VERSION 5.7 ;
  NOWIREEXTENSIONATPIN ON ;
  DIVIDERCHAR "/" ;
  BUSBITCHARS "[]" ;
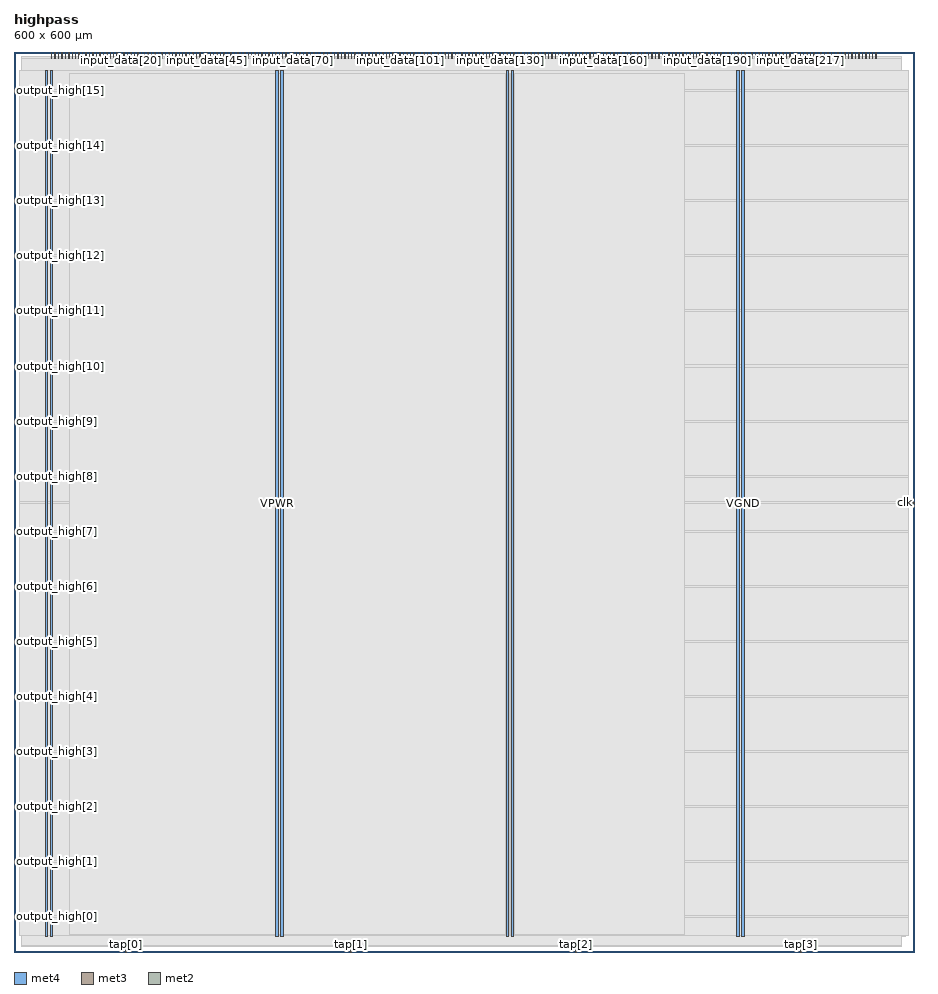
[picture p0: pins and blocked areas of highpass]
MACRO highpass
  CLASS BLOCK ;
  FOREIGN highpass ;
  ORIGIN 0.000 0.000 ;
  SIZE 600.000 BY 600.000 ;
  PIN VGND
    DIRECTION INOUT ;
    USE GROUND ;
    PORT
      LAYER met4 ;
        RECT 24.340 10.640 25.940 587.760 ;
    END
    PORT
      LAYER met4 ;
        RECT 177.940 10.640 179.540 587.760 ;
    END
    PORT
      LAYER met4 ;
        RECT 331.540 10.640 333.140 587.760 ;
    END
    PORT
      LAYER met4 ;
        RECT 485.140 10.640 486.740 587.760 ;
    END
  END VGND
  PIN VPWR
    DIRECTION INOUT ;
    USE POWER ;
    PORT
      LAYER met4 ;
        RECT 21.040 10.640 22.640 587.760 ;
    END
    PORT
      LAYER met4 ;
        RECT 174.640 10.640 176.240 587.760 ;
    END
    PORT
      LAYER met4 ;
        RECT 328.240 10.640 329.840 587.760 ;
    END
    PORT
      LAYER met4 ;
        RECT 481.840 10.640 483.440 587.760 ;
    END
  END VPWR
  PIN clk
    DIRECTION INPUT ;
    USE SIGNAL ;
    ANTENNAGATEAREA 0.852000 ;
    ANTENNADIFFAREA 0.434700 ;
    PORT
      LAYER met3 ;
        RECT 596.000 299.240 600.000 299.840 ;
    END
  END clk
  PIN input_data[0]
    DIRECTION INPUT ;
    USE SIGNAL ;
    ANTENNAGATEAREA 0.247500 ;
    ANTENNADIFFAREA 0.434700 ;
    PORT
      LAYER met2 ;
        RECT 24.930 596.000 25.210 600.000 ;
    END
  END input_data[0]
  PIN input_data[100]
    DIRECTION INPUT ;
    USE SIGNAL ;
    ANTENNAGATEAREA 0.213000 ;
    ANTENNADIFFAREA 0.434700 ;
    PORT
      LAYER met2 ;
        RECT 254.930 596.000 255.210 600.000 ;
    END
  END input_data[100]
  PIN input_data[101]
    DIRECTION INPUT ;
    USE SIGNAL ;
    ANTENNAGATEAREA 0.196500 ;
    ANTENNADIFFAREA 0.434700 ;
    PORT
      LAYER met2 ;
        RECT 257.230 596.000 257.510 600.000 ;
    END
  END input_data[101]
  PIN input_data[102]
    DIRECTION INPUT ;
    USE SIGNAL ;
    ANTENNAGATEAREA 0.196500 ;
    ANTENNADIFFAREA 0.434700 ;
    PORT
      LAYER met2 ;
        RECT 259.530 596.000 259.810 600.000 ;
    END
  END input_data[102]
  PIN input_data[103]
    DIRECTION INPUT ;
    USE SIGNAL ;
    ANTENNAGATEAREA 0.196500 ;
    ANTENNADIFFAREA 0.434700 ;
    PORT
      LAYER met2 ;
        RECT 261.830 596.000 262.110 600.000 ;
    END
  END input_data[103]
  PIN input_data[104]
    DIRECTION INPUT ;
    USE SIGNAL ;
    ANTENNAGATEAREA 0.196500 ;
    ANTENNADIFFAREA 0.434700 ;
    PORT
      LAYER met2 ;
        RECT 264.130 596.000 264.410 600.000 ;
    END
  END input_data[104]
  PIN input_data[105]
    DIRECTION INPUT ;
    USE SIGNAL ;
    ANTENNAGATEAREA 0.196500 ;
    ANTENNADIFFAREA 0.434700 ;
    PORT
      LAYER met2 ;
        RECT 266.430 596.000 266.710 600.000 ;
    END
  END input_data[105]
  PIN input_data[106]
    DIRECTION INPUT ;
    USE SIGNAL ;
    ANTENNAGATEAREA 0.196500 ;
    ANTENNADIFFAREA 0.434700 ;
    PORT
      LAYER met2 ;
        RECT 268.730 596.000 269.010 600.000 ;
    END
  END input_data[106]
  PIN input_data[107]
    DIRECTION INPUT ;
    USE SIGNAL ;
    ANTENNAGATEAREA 0.196500 ;
    ANTENNADIFFAREA 0.434700 ;
    PORT
      LAYER met2 ;
        RECT 271.030 596.000 271.310 600.000 ;
    END
  END input_data[107]
  PIN input_data[108]
    DIRECTION INPUT ;
    USE SIGNAL ;
    ANTENNAGATEAREA 0.213000 ;
    ANTENNADIFFAREA 0.434700 ;
    PORT
      LAYER met2 ;
        RECT 273.330 596.000 273.610 600.000 ;
    END
  END input_data[108]
  PIN input_data[109]
    DIRECTION INPUT ;
    USE SIGNAL ;
    ANTENNAGATEAREA 0.126000 ;
    ANTENNADIFFAREA 0.434700 ;
    PORT
      LAYER met2 ;
        RECT 275.630 596.000 275.910 600.000 ;
    END
  END input_data[109]
  PIN input_data[10]
    DIRECTION INPUT ;
    USE SIGNAL ;
    ANTENNAGATEAREA 0.247500 ;
    ANTENNADIFFAREA 0.434700 ;
    PORT
      LAYER met2 ;
        RECT 47.930 596.000 48.210 600.000 ;
    END
  END input_data[10]
  PIN input_data[110]
    DIRECTION INPUT ;
    USE SIGNAL ;
    ANTENNAGATEAREA 0.196500 ;
    ANTENNADIFFAREA 0.434700 ;
    PORT
      LAYER met2 ;
        RECT 277.930 596.000 278.210 600.000 ;
    END
  END input_data[110]
  PIN input_data[111]
    DIRECTION INPUT ;
    USE SIGNAL ;
    ANTENNAGATEAREA 0.196500 ;
    ANTENNADIFFAREA 0.434700 ;
    PORT
      LAYER met2 ;
        RECT 280.230 596.000 280.510 600.000 ;
    END
  END input_data[111]
  PIN input_data[112]
    DIRECTION INPUT ;
    USE SIGNAL ;
    ANTENNAGATEAREA 0.213000 ;
    ANTENNADIFFAREA 0.434700 ;
    PORT
      LAYER met2 ;
        RECT 282.530 596.000 282.810 600.000 ;
    END
  END input_data[112]
  PIN input_data[113]
    DIRECTION INPUT ;
    USE SIGNAL ;
    ANTENNAGATEAREA 0.126000 ;
    ANTENNADIFFAREA 0.434700 ;
    PORT
      LAYER met2 ;
        RECT 284.830 596.000 285.110 600.000 ;
    END
  END input_data[113]
  PIN input_data[114]
    DIRECTION INPUT ;
    USE SIGNAL ;
    ANTENNAGATEAREA 0.126000 ;
    ANTENNADIFFAREA 0.434700 ;
    PORT
      LAYER met2 ;
        RECT 287.130 596.000 287.410 600.000 ;
    END
  END input_data[114]
  PIN input_data[115]
    DIRECTION INPUT ;
    USE SIGNAL ;
    ANTENNAGATEAREA 0.196500 ;
    ANTENNADIFFAREA 0.434700 ;
    PORT
      LAYER met2 ;
        RECT 289.430 596.000 289.710 600.000 ;
    END
  END input_data[115]
  PIN input_data[116]
    DIRECTION INPUT ;
    USE SIGNAL ;
    ANTENNAGATEAREA 0.196500 ;
    ANTENNADIFFAREA 0.434700 ;
    PORT
      LAYER met2 ;
        RECT 291.730 596.000 292.010 600.000 ;
    END
  END input_data[116]
  PIN input_data[117]
    DIRECTION INPUT ;
    USE SIGNAL ;
    ANTENNAGATEAREA 0.196500 ;
    ANTENNADIFFAREA 0.434700 ;
    PORT
      LAYER met2 ;
        RECT 294.030 596.000 294.310 600.000 ;
    END
  END input_data[117]
  PIN input_data[118]
    DIRECTION INPUT ;
    USE SIGNAL ;
    ANTENNAGATEAREA 0.196500 ;
    ANTENNADIFFAREA 0.434700 ;
    PORT
      LAYER met2 ;
        RECT 296.330 596.000 296.610 600.000 ;
    END
  END input_data[118]
  PIN input_data[119]
    DIRECTION INPUT ;
    USE SIGNAL ;
    ANTENNAGATEAREA 0.196500 ;
    ANTENNADIFFAREA 0.434700 ;
    PORT
      LAYER met2 ;
        RECT 298.630 596.000 298.910 600.000 ;
    END
  END input_data[119]
  PIN input_data[11]
    DIRECTION INPUT ;
    USE SIGNAL ;
    ANTENNAGATEAREA 0.159000 ;
    ANTENNADIFFAREA 0.434700 ;
    PORT
      LAYER met2 ;
        RECT 50.230 596.000 50.510 600.000 ;
    END
  END input_data[11]
  PIN input_data[120]
    DIRECTION INPUT ;
    USE SIGNAL ;
    ANTENNAGATEAREA 0.213000 ;
    ANTENNADIFFAREA 0.434700 ;
    PORT
      LAYER met2 ;
        RECT 300.930 596.000 301.210 600.000 ;
    END
  END input_data[120]
  PIN input_data[121]
    DIRECTION INPUT ;
    USE SIGNAL ;
    ANTENNAGATEAREA 0.126000 ;
    ANTENNADIFFAREA 0.434700 ;
    PORT
      LAYER met2 ;
        RECT 303.230 596.000 303.510 600.000 ;
    END
  END input_data[121]
  PIN input_data[122]
    DIRECTION INPUT ;
    USE SIGNAL ;
    ANTENNAGATEAREA 0.159000 ;
    ANTENNADIFFAREA 0.434700 ;
    PORT
      LAYER met2 ;
        RECT 305.530 596.000 305.810 600.000 ;
    END
  END input_data[122]
  PIN input_data[123]
    DIRECTION INPUT ;
    USE SIGNAL ;
    ANTENNAGATEAREA 0.159000 ;
    ANTENNADIFFAREA 0.434700 ;
    PORT
      LAYER met2 ;
        RECT 307.830 596.000 308.110 600.000 ;
    END
  END input_data[123]
  PIN input_data[124]
    DIRECTION INPUT ;
    USE SIGNAL ;
    ANTENNAGATEAREA 0.213000 ;
    ANTENNADIFFAREA 0.434700 ;
    PORT
      LAYER met2 ;
        RECT 310.130 596.000 310.410 600.000 ;
    END
  END input_data[124]
  PIN input_data[125]
    DIRECTION INPUT ;
    USE SIGNAL ;
    ANTENNAGATEAREA 0.196500 ;
    ANTENNADIFFAREA 0.434700 ;
    PORT
      LAYER met2 ;
        RECT 312.430 596.000 312.710 600.000 ;
    END
  END input_data[125]
  PIN input_data[126]
    DIRECTION INPUT ;
    USE SIGNAL ;
    ANTENNAGATEAREA 0.196500 ;
    ANTENNADIFFAREA 0.434700 ;
    PORT
      LAYER met2 ;
        RECT 314.730 596.000 315.010 600.000 ;
    END
  END input_data[126]
  PIN input_data[127]
    DIRECTION INPUT ;
    USE SIGNAL ;
    PORT
      LAYER met2 ;
        RECT 317.030 596.000 317.310 600.000 ;
    END
  END input_data[127]
  PIN input_data[128]
    DIRECTION INPUT ;
    USE SIGNAL ;
    ANTENNAGATEAREA 0.213000 ;
    ANTENNADIFFAREA 0.434700 ;
    PORT
      LAYER met2 ;
        RECT 319.330 596.000 319.610 600.000 ;
    END
  END input_data[128]
  PIN input_data[129]
    DIRECTION INPUT ;
    USE SIGNAL ;
    ANTENNAGATEAREA 0.213000 ;
    ANTENNADIFFAREA 0.434700 ;
    PORT
      LAYER met2 ;
        RECT 321.630 596.000 321.910 600.000 ;
    END
  END input_data[129]
  PIN input_data[12]
    DIRECTION INPUT ;
    USE SIGNAL ;
    ANTENNAGATEAREA 0.742500 ;
    ANTENNADIFFAREA 0.434700 ;
    PORT
      LAYER met2 ;
        RECT 52.530 596.000 52.810 600.000 ;
    END
  END input_data[12]
  PIN input_data[130]
    DIRECTION INPUT ;
    USE SIGNAL ;
    ANTENNAGATEAREA 0.159000 ;
    ANTENNADIFFAREA 0.434700 ;
    PORT
      LAYER met2 ;
        RECT 323.930 596.000 324.210 600.000 ;
    END
  END input_data[130]
  PIN input_data[131]
    DIRECTION INPUT ;
    USE SIGNAL ;
    ANTENNAGATEAREA 0.159000 ;
    ANTENNADIFFAREA 0.434700 ;
    PORT
      LAYER met2 ;
        RECT 326.230 596.000 326.510 600.000 ;
    END
  END input_data[131]
  PIN input_data[132]
    DIRECTION INPUT ;
    USE SIGNAL ;
    ANTENNAGATEAREA 0.159000 ;
    ANTENNADIFFAREA 0.434700 ;
    PORT
      LAYER met2 ;
        RECT 328.530 596.000 328.810 600.000 ;
    END
  END input_data[132]
  PIN input_data[133]
    DIRECTION INPUT ;
    USE SIGNAL ;
    ANTENNAGATEAREA 0.247500 ;
    ANTENNADIFFAREA 0.434700 ;
    PORT
      LAYER met2 ;
        RECT 330.830 596.000 331.110 600.000 ;
    END
  END input_data[133]
  PIN input_data[134]
    DIRECTION INPUT ;
    USE SIGNAL ;
    ANTENNAGATEAREA 0.247500 ;
    ANTENNADIFFAREA 0.434700 ;
    PORT
      LAYER met2 ;
        RECT 333.130 596.000 333.410 600.000 ;
    END
  END input_data[134]
  PIN input_data[135]
    DIRECTION INPUT ;
    USE SIGNAL ;
    ANTENNAGATEAREA 0.247500 ;
    ANTENNADIFFAREA 0.434700 ;
    PORT
      LAYER met2 ;
        RECT 335.430 596.000 335.710 600.000 ;
    END
  END input_data[135]
  PIN input_data[136]
    DIRECTION INPUT ;
    USE SIGNAL ;
    ANTENNAGATEAREA 0.742500 ;
    ANTENNADIFFAREA 0.434700 ;
    PORT
      LAYER met2 ;
        RECT 337.730 596.000 338.010 600.000 ;
    END
  END input_data[136]
  PIN input_data[137]
    DIRECTION INPUT ;
    USE SIGNAL ;
    ANTENNAGATEAREA 0.426000 ;
    ANTENNADIFFAREA 0.434700 ;
    PORT
      LAYER met2 ;
        RECT 340.030 596.000 340.310 600.000 ;
    END
  END input_data[137]
  PIN input_data[138]
    DIRECTION INPUT ;
    USE SIGNAL ;
    ANTENNAGATEAREA 0.213000 ;
    ANTENNADIFFAREA 0.434700 ;
    PORT
      LAYER met2 ;
        RECT 342.330 596.000 342.610 600.000 ;
    END
  END input_data[138]
  PIN input_data[139]
    DIRECTION INPUT ;
    USE SIGNAL ;
    ANTENNAGATEAREA 0.426000 ;
    ANTENNADIFFAREA 0.434700 ;
    PORT
      LAYER met2 ;
        RECT 344.630 596.000 344.910 600.000 ;
    END
  END input_data[139]
  PIN input_data[13]
    DIRECTION INPUT ;
    USE SIGNAL ;
    ANTENNAGATEAREA 0.495000 ;
    ANTENNADIFFAREA 0.434700 ;
    PORT
      LAYER met2 ;
        RECT 54.830 596.000 55.110 600.000 ;
    END
  END input_data[13]
  PIN input_data[140]
    DIRECTION INPUT ;
    USE SIGNAL ;
    ANTENNAGATEAREA 0.247500 ;
    ANTENNADIFFAREA 0.434700 ;
    PORT
      LAYER met2 ;
        RECT 346.930 596.000 347.210 600.000 ;
    END
  END input_data[140]
  PIN input_data[141]
    DIRECTION INPUT ;
    USE SIGNAL ;
    ANTENNAGATEAREA 0.247500 ;
    ANTENNADIFFAREA 0.434700 ;
    PORT
      LAYER met2 ;
        RECT 349.230 596.000 349.510 600.000 ;
    END
  END input_data[141]
  PIN input_data[142]
    DIRECTION INPUT ;
    USE SIGNAL ;
    ANTENNAGATEAREA 0.213000 ;
    ANTENNADIFFAREA 0.434700 ;
    PORT
      LAYER met2 ;
        RECT 351.530 596.000 351.810 600.000 ;
    END
  END input_data[142]
  PIN input_data[143]
    DIRECTION INPUT ;
    USE SIGNAL ;
    ANTENNAGATEAREA 0.213000 ;
    ANTENNADIFFAREA 0.434700 ;
    PORT
      LAYER met2 ;
        RECT 353.830 596.000 354.110 600.000 ;
    END
  END input_data[143]
  PIN input_data[144]
    DIRECTION INPUT ;
    USE SIGNAL ;
    ANTENNAGATEAREA 0.213000 ;
    ANTENNADIFFAREA 0.434700 ;
    PORT
      LAYER met2 ;
        RECT 356.130 596.000 356.410 600.000 ;
    END
  END input_data[144]
  PIN input_data[145]
    DIRECTION INPUT ;
    USE SIGNAL ;
    ANTENNAGATEAREA 0.213000 ;
    ANTENNADIFFAREA 0.434700 ;
    PORT
      LAYER met2 ;
        RECT 358.430 596.000 358.710 600.000 ;
    END
  END input_data[145]
  PIN input_data[146]
    DIRECTION INPUT ;
    USE SIGNAL ;
    ANTENNAGATEAREA 0.213000 ;
    ANTENNADIFFAREA 0.434700 ;
    PORT
      LAYER met2 ;
        RECT 360.730 596.000 361.010 600.000 ;
    END
  END input_data[146]
  PIN input_data[147]
    DIRECTION INPUT ;
    USE SIGNAL ;
    ANTENNAGATEAREA 0.159000 ;
    ANTENNADIFFAREA 0.434700 ;
    PORT
      LAYER met2 ;
        RECT 363.030 596.000 363.310 600.000 ;
    END
  END input_data[147]
  PIN input_data[148]
    DIRECTION INPUT ;
    USE SIGNAL ;
    ANTENNAGATEAREA 0.213000 ;
    ANTENNADIFFAREA 0.434700 ;
    PORT
      LAYER met2 ;
        RECT 365.330 596.000 365.610 600.000 ;
    END
  END input_data[148]
  PIN input_data[149]
    DIRECTION INPUT ;
    USE SIGNAL ;
    ANTENNAGATEAREA 0.213000 ;
    ANTENNADIFFAREA 0.434700 ;
    PORT
      LAYER met2 ;
        RECT 367.630 596.000 367.910 600.000 ;
    END
  END input_data[149]
  PIN input_data[14]
    DIRECTION INPUT ;
    USE SIGNAL ;
    ANTENNAGATEAREA 0.159000 ;
    ANTENNADIFFAREA 0.434700 ;
    PORT
      LAYER met2 ;
        RECT 57.130 596.000 57.410 600.000 ;
    END
  END input_data[14]
  PIN input_data[150]
    DIRECTION INPUT ;
    USE SIGNAL ;
    ANTENNAGATEAREA 0.213000 ;
    ANTENNADIFFAREA 0.434700 ;
    PORT
      LAYER met2 ;
        RECT 369.930 596.000 370.210 600.000 ;
    END
  END input_data[150]
  PIN input_data[151]
    DIRECTION INPUT ;
    USE SIGNAL ;
    ANTENNAGATEAREA 0.159000 ;
    ANTENNADIFFAREA 0.434700 ;
    PORT
      LAYER met2 ;
        RECT 372.230 596.000 372.510 600.000 ;
    END
  END input_data[151]
  PIN input_data[152]
    DIRECTION INPUT ;
    USE SIGNAL ;
    ANTENNAGATEAREA 0.159000 ;
    ANTENNADIFFAREA 0.434700 ;
    PORT
      LAYER met2 ;
        RECT 374.530 596.000 374.810 600.000 ;
    END
  END input_data[152]
  PIN input_data[153]
    DIRECTION INPUT ;
    USE SIGNAL ;
    ANTENNAGATEAREA 0.213000 ;
    ANTENNADIFFAREA 0.434700 ;
    PORT
      LAYER met2 ;
        RECT 376.830 596.000 377.110 600.000 ;
    END
  END input_data[153]
  PIN input_data[154]
    DIRECTION INPUT ;
    USE SIGNAL ;
    ANTENNAGATEAREA 0.213000 ;
    ANTENNADIFFAREA 0.434700 ;
    PORT
      LAYER met2 ;
        RECT 379.130 596.000 379.410 600.000 ;
    END
  END input_data[154]
  PIN input_data[155]
    DIRECTION INPUT ;
    USE SIGNAL ;
    ANTENNAGATEAREA 0.196500 ;
    ANTENNADIFFAREA 0.434700 ;
    PORT
      LAYER met2 ;
        RECT 381.430 596.000 381.710 600.000 ;
    END
  END input_data[155]
  PIN input_data[156]
    DIRECTION INPUT ;
    USE SIGNAL ;
    ANTENNAGATEAREA 0.213000 ;
    ANTENNADIFFAREA 0.434700 ;
    PORT
      LAYER met2 ;
        RECT 383.730 596.000 384.010 600.000 ;
    END
  END input_data[156]
  PIN input_data[157]
    DIRECTION INPUT ;
    USE SIGNAL ;
    ANTENNAGATEAREA 0.213000 ;
    ANTENNADIFFAREA 0.434700 ;
    PORT
      LAYER met2 ;
        RECT 386.030 596.000 386.310 600.000 ;
    END
  END input_data[157]
  PIN input_data[158]
    DIRECTION INPUT ;
    USE SIGNAL ;
    ANTENNAGATEAREA 0.196500 ;
    ANTENNADIFFAREA 0.434700 ;
    PORT
      LAYER met2 ;
        RECT 388.330 596.000 388.610 600.000 ;
    END
  END input_data[158]
  PIN input_data[159]
    DIRECTION INPUT ;
    USE SIGNAL ;
    ANTENNAGATEAREA 0.196500 ;
    ANTENNADIFFAREA 0.434700 ;
    PORT
      LAYER met2 ;
        RECT 390.630 596.000 390.910 600.000 ;
    END
  END input_data[159]
  PIN input_data[15]
    DIRECTION INPUT ;
    USE SIGNAL ;
    ANTENNAGATEAREA 0.213000 ;
    ANTENNADIFFAREA 0.434700 ;
    PORT
      LAYER met2 ;
        RECT 59.430 596.000 59.710 600.000 ;
    END
  END input_data[15]
  PIN input_data[160]
    DIRECTION INPUT ;
    USE SIGNAL ;
    ANTENNAGATEAREA 0.426000 ;
    ANTENNADIFFAREA 0.434700 ;
    PORT
      LAYER met2 ;
        RECT 392.930 596.000 393.210 600.000 ;
    END
  END input_data[160]
  PIN input_data[161]
    DIRECTION INPUT ;
    USE SIGNAL ;
    ANTENNAGATEAREA 0.247500 ;
    ANTENNADIFFAREA 0.434700 ;
    PORT
      LAYER met2 ;
        RECT 395.230 596.000 395.510 600.000 ;
    END
  END input_data[161]
  PIN input_data[162]
    DIRECTION INPUT ;
    USE SIGNAL ;
    ANTENNAGATEAREA 0.247500 ;
    ANTENNADIFFAREA 0.434700 ;
    PORT
      LAYER met2 ;
        RECT 397.530 596.000 397.810 600.000 ;
    END
  END input_data[162]
  PIN input_data[163]
    DIRECTION INPUT ;
    USE SIGNAL ;
    ANTENNAGATEAREA 0.247500 ;
    ANTENNADIFFAREA 0.434700 ;
    PORT
      LAYER met2 ;
        RECT 399.830 596.000 400.110 600.000 ;
    END
  END input_data[163]
  PIN input_data[164]
    DIRECTION INPUT ;
    USE SIGNAL ;
    ANTENNAGATEAREA 0.213000 ;
    ANTENNADIFFAREA 0.434700 ;
    PORT
      LAYER met2 ;
        RECT 402.130 596.000 402.410 600.000 ;
    END
  END input_data[164]
  PIN input_data[165]
    DIRECTION INPUT ;
    USE SIGNAL ;
    ANTENNAGATEAREA 0.213000 ;
    ANTENNADIFFAREA 0.434700 ;
    PORT
      LAYER met2 ;
        RECT 404.430 596.000 404.710 600.000 ;
    END
  END input_data[165]
  PIN input_data[166]
    DIRECTION INPUT ;
    USE SIGNAL ;
    ANTENNAGATEAREA 0.213000 ;
    ANTENNADIFFAREA 0.434700 ;
    PORT
      LAYER met2 ;
        RECT 406.730 596.000 407.010 600.000 ;
    END
  END input_data[166]
  PIN input_data[167]
    DIRECTION INPUT ;
    USE SIGNAL ;
    ANTENNAGATEAREA 0.126000 ;
    ANTENNADIFFAREA 0.434700 ;
    PORT
      LAYER met2 ;
        RECT 409.030 596.000 409.310 600.000 ;
    END
  END input_data[167]
  PIN input_data[168]
    DIRECTION INPUT ;
    USE SIGNAL ;
    ANTENNAGATEAREA 0.126000 ;
    ANTENNADIFFAREA 0.434700 ;
    PORT
      LAYER met2 ;
        RECT 411.330 596.000 411.610 600.000 ;
    END
  END input_data[168]
  PIN input_data[169]
    DIRECTION INPUT ;
    USE SIGNAL ;
    ANTENNAGATEAREA 0.196500 ;
    ANTENNADIFFAREA 0.434700 ;
    PORT
      LAYER met2 ;
        RECT 413.630 596.000 413.910 600.000 ;
    END
  END input_data[169]
  PIN input_data[16]
    DIRECTION INPUT ;
    USE SIGNAL ;
    ANTENNAGATEAREA 0.247500 ;
    ANTENNADIFFAREA 0.434700 ;
    PORT
      LAYER met2 ;
        RECT 61.730 596.000 62.010 600.000 ;
    END
  END input_data[16]
  PIN input_data[170]
    DIRECTION INPUT ;
    USE SIGNAL ;
    ANTENNAGATEAREA 0.196500 ;
    ANTENNADIFFAREA 0.434700 ;
    PORT
      LAYER met2 ;
        RECT 415.930 596.000 416.210 600.000 ;
    END
  END input_data[170]
  PIN input_data[171]
    DIRECTION INPUT ;
    USE SIGNAL ;
    ANTENNAGATEAREA 0.213000 ;
    ANTENNADIFFAREA 0.434700 ;
    PORT
      LAYER met2 ;
        RECT 418.230 596.000 418.510 600.000 ;
    END
  END input_data[171]
  PIN input_data[172]
    DIRECTION INPUT ;
    USE SIGNAL ;
    ANTENNAGATEAREA 0.159000 ;
    ANTENNADIFFAREA 0.434700 ;
    PORT
      LAYER met2 ;
        RECT 420.530 596.000 420.810 600.000 ;
    END
  END input_data[172]
  PIN input_data[173]
    DIRECTION INPUT ;
    USE SIGNAL ;
    ANTENNAGATEAREA 0.213000 ;
    ANTENNADIFFAREA 0.434700 ;
    PORT
      LAYER met2 ;
        RECT 422.830 596.000 423.110 600.000 ;
    END
  END input_data[173]
  PIN input_data[174]
    DIRECTION INPUT ;
    USE SIGNAL ;
    ANTENNAGATEAREA 0.196500 ;
    ANTENNADIFFAREA 0.434700 ;
    PORT
      LAYER met2 ;
        RECT 425.130 596.000 425.410 600.000 ;
    END
  END input_data[174]
  PIN input_data[175]
    DIRECTION INPUT ;
    USE SIGNAL ;
    ANTENNAGATEAREA 0.196500 ;
    ANTENNADIFFAREA 0.434700 ;
    PORT
      LAYER met2 ;
        RECT 427.430 596.000 427.710 600.000 ;
    END
  END input_data[175]
  PIN input_data[176]
    DIRECTION INPUT ;
    USE SIGNAL ;
    ANTENNAGATEAREA 0.213000 ;
    ANTENNADIFFAREA 0.434700 ;
    PORT
      LAYER met2 ;
        RECT 429.730 596.000 430.010 600.000 ;
    END
  END input_data[176]
  PIN input_data[177]
    DIRECTION INPUT ;
    USE SIGNAL ;
    ANTENNAGATEAREA 0.213000 ;
    ANTENNADIFFAREA 0.434700 ;
    PORT
      LAYER met2 ;
        RECT 432.030 596.000 432.310 600.000 ;
    END
  END input_data[177]
  PIN input_data[178]
    DIRECTION INPUT ;
    USE SIGNAL ;
    ANTENNAGATEAREA 0.213000 ;
    ANTENNADIFFAREA 0.434700 ;
    PORT
      LAYER met2 ;
        RECT 434.330 596.000 434.610 600.000 ;
    END
  END input_data[178]
  PIN input_data[179]
    DIRECTION INPUT ;
    USE SIGNAL ;
    ANTENNAGATEAREA 0.247500 ;
    ANTENNADIFFAREA 0.434700 ;
    PORT
      LAYER met2 ;
        RECT 436.630 596.000 436.910 600.000 ;
    END
  END input_data[179]
  PIN input_data[17]
    DIRECTION INPUT ;
    USE SIGNAL ;
    ANTENNAGATEAREA 0.213000 ;
    ANTENNADIFFAREA 0.434700 ;
    PORT
      LAYER met2 ;
        RECT 64.030 596.000 64.310 600.000 ;
    END
  END input_data[17]
  PIN input_data[180]
    DIRECTION INPUT ;
    USE SIGNAL ;
    ANTENNAGATEAREA 0.213000 ;
    ANTENNADIFFAREA 0.434700 ;
    PORT
      LAYER met2 ;
        RECT 438.930 596.000 439.210 600.000 ;
    END
  END input_data[180]
  PIN input_data[181]
    DIRECTION INPUT ;
    USE SIGNAL ;
    ANTENNAGATEAREA 0.159000 ;
    ANTENNADIFFAREA 0.434700 ;
    PORT
      LAYER met2 ;
        RECT 441.230 596.000 441.510 600.000 ;
    END
  END input_data[181]
  PIN input_data[182]
    DIRECTION INPUT ;
    USE SIGNAL ;
    ANTENNAGATEAREA 0.159000 ;
    ANTENNADIFFAREA 0.434700 ;
    PORT
      LAYER met2 ;
        RECT 443.530 596.000 443.810 600.000 ;
    END
  END input_data[182]
  PIN input_data[183]
    DIRECTION INPUT ;
    USE SIGNAL ;
    ANTENNAGATEAREA 0.159000 ;
    ANTENNADIFFAREA 0.434700 ;
    PORT
      LAYER met2 ;
        RECT 445.830 596.000 446.110 600.000 ;
    END
  END input_data[183]
  PIN input_data[184]
    DIRECTION INPUT ;
    USE SIGNAL ;
    ANTENNAGATEAREA 0.159000 ;
    ANTENNADIFFAREA 0.434700 ;
    PORT
      LAYER met2 ;
        RECT 448.130 596.000 448.410 600.000 ;
    END
  END input_data[184]
  PIN input_data[185]
    DIRECTION INPUT ;
    USE SIGNAL ;
    ANTENNAGATEAREA 0.213000 ;
    ANTENNADIFFAREA 0.434700 ;
    PORT
      LAYER met2 ;
        RECT 450.430 596.000 450.710 600.000 ;
    END
  END input_data[185]
  PIN input_data[186]
    DIRECTION INPUT ;
    USE SIGNAL ;
    ANTENNAGATEAREA 0.213000 ;
    ANTENNADIFFAREA 0.434700 ;
    PORT
      LAYER met2 ;
        RECT 452.730 596.000 453.010 600.000 ;
    END
  END input_data[186]
  PIN input_data[187]
    DIRECTION INPUT ;
    USE SIGNAL ;
    ANTENNAGATEAREA 0.159000 ;
    ANTENNADIFFAREA 0.434700 ;
    PORT
      LAYER met2 ;
        RECT 455.030 596.000 455.310 600.000 ;
    END
  END input_data[187]
  PIN input_data[188]
    DIRECTION INPUT ;
    USE SIGNAL ;
    ANTENNAGATEAREA 0.213000 ;
    ANTENNADIFFAREA 0.434700 ;
    PORT
      LAYER met2 ;
        RECT 457.330 596.000 457.610 600.000 ;
    END
  END input_data[188]
  PIN input_data[189]
    DIRECTION INPUT ;
    USE SIGNAL ;
    ANTENNAGATEAREA 0.196500 ;
    ANTENNADIFFAREA 0.434700 ;
    PORT
      LAYER met2 ;
        RECT 459.630 596.000 459.910 600.000 ;
    END
  END input_data[189]
  PIN input_data[18]
    DIRECTION INPUT ;
    USE SIGNAL ;
    ANTENNAGATEAREA 0.247500 ;
    ANTENNADIFFAREA 0.434700 ;
    PORT
      LAYER met2 ;
        RECT 66.330 596.000 66.610 600.000 ;
    END
  END input_data[18]
  PIN input_data[190]
    DIRECTION INPUT ;
    USE SIGNAL ;
    ANTENNAGATEAREA 0.196500 ;
    ANTENNADIFFAREA 0.434700 ;
    PORT
      LAYER met2 ;
        RECT 461.930 596.000 462.210 600.000 ;
    END
  END input_data[190]
  PIN input_data[191]
    DIRECTION INPUT ;
    USE SIGNAL ;
    PORT
      LAYER met2 ;
        RECT 464.230 596.000 464.510 600.000 ;
    END
  END input_data[191]
  PIN input_data[192]
    DIRECTION INPUT ;
    USE SIGNAL ;
    ANTENNAGATEAREA 0.159000 ;
    ANTENNADIFFAREA 0.434700 ;
    PORT
      LAYER met2 ;
        RECT 466.530 596.000 466.810 600.000 ;
    END
  END input_data[192]
  PIN input_data[193]
    DIRECTION INPUT ;
    USE SIGNAL ;
    ANTENNAGATEAREA 0.213000 ;
    ANTENNADIFFAREA 0.434700 ;
    PORT
      LAYER met2 ;
        RECT 468.830 596.000 469.110 600.000 ;
    END
  END input_data[193]
  PIN input_data[194]
    DIRECTION INPUT ;
    USE SIGNAL ;
    ANTENNAGATEAREA 0.213000 ;
    ANTENNADIFFAREA 0.434700 ;
    PORT
      LAYER met2 ;
        RECT 471.130 596.000 471.410 600.000 ;
    END
  END input_data[194]
  PIN input_data[195]
    DIRECTION INPUT ;
    USE SIGNAL ;
    ANTENNAGATEAREA 0.159000 ;
    ANTENNADIFFAREA 0.434700 ;
    PORT
      LAYER met2 ;
        RECT 473.430 596.000 473.710 600.000 ;
    END
  END input_data[195]
  PIN input_data[196]
    DIRECTION INPUT ;
    USE SIGNAL ;
    ANTENNAGATEAREA 0.213000 ;
    ANTENNADIFFAREA 0.434700 ;
    PORT
      LAYER met2 ;
        RECT 475.730 596.000 476.010 600.000 ;
    END
  END input_data[196]
  PIN input_data[197]
    DIRECTION INPUT ;
    USE SIGNAL ;
    ANTENNAGATEAREA 0.126000 ;
    ANTENNADIFFAREA 0.434700 ;
    PORT
      LAYER met2 ;
        RECT 478.030 596.000 478.310 600.000 ;
    END
  END input_data[197]
  PIN input_data[198]
    DIRECTION INPUT ;
    USE SIGNAL ;
    ANTENNAGATEAREA 0.126000 ;
    ANTENNADIFFAREA 0.434700 ;
    PORT
      LAYER met2 ;
        RECT 480.330 596.000 480.610 600.000 ;
    END
  END input_data[198]
  PIN input_data[199]
    DIRECTION INPUT ;
    USE SIGNAL ;
    ANTENNAGATEAREA 0.213000 ;
    ANTENNADIFFAREA 0.434700 ;
    PORT
      LAYER met2 ;
        RECT 482.630 596.000 482.910 600.000 ;
    END
  END input_data[199]
  PIN input_data[19]
    DIRECTION INPUT ;
    USE SIGNAL ;
    ANTENNAGATEAREA 0.247500 ;
    ANTENNADIFFAREA 0.434700 ;
    PORT
      LAYER met2 ;
        RECT 68.630 596.000 68.910 600.000 ;
    END
  END input_data[19]
  PIN input_data[1]
    DIRECTION INPUT ;
    USE SIGNAL ;
    ANTENNAGATEAREA 0.213000 ;
    ANTENNADIFFAREA 0.434700 ;
    PORT
      LAYER met2 ;
        RECT 27.230 596.000 27.510 600.000 ;
    END
  END input_data[1]
  PIN input_data[200]
    DIRECTION INPUT ;
    USE SIGNAL ;
    ANTENNAGATEAREA 0.213000 ;
    ANTENNADIFFAREA 0.434700 ;
    PORT
      LAYER met2 ;
        RECT 484.930 596.000 485.210 600.000 ;
    END
  END input_data[200]
  PIN input_data[201]
    DIRECTION INPUT ;
    USE SIGNAL ;
    ANTENNAGATEAREA 0.213000 ;
    ANTENNADIFFAREA 0.434700 ;
    PORT
      LAYER met2 ;
        RECT 487.230 596.000 487.510 600.000 ;
    END
  END input_data[201]
  PIN input_data[202]
    DIRECTION INPUT ;
    USE SIGNAL ;
    ANTENNAGATEAREA 0.213000 ;
    ANTENNADIFFAREA 0.434700 ;
    PORT
      LAYER met2 ;
        RECT 489.530 596.000 489.810 600.000 ;
    END
  END input_data[202]
  PIN input_data[203]
    DIRECTION INPUT ;
    USE SIGNAL ;
    ANTENNAGATEAREA 0.213000 ;
    ANTENNADIFFAREA 0.434700 ;
    PORT
      LAYER met2 ;
        RECT 491.830 596.000 492.110 600.000 ;
    END
  END input_data[203]
  PIN input_data[204]
    DIRECTION INPUT ;
    USE SIGNAL ;
    ANTENNAGATEAREA 0.196500 ;
    ANTENNADIFFAREA 0.434700 ;
    PORT
      LAYER met2 ;
        RECT 494.130 596.000 494.410 600.000 ;
    END
  END input_data[204]
  PIN input_data[205]
    DIRECTION INPUT ;
    USE SIGNAL ;
    ANTENNAGATEAREA 0.196500 ;
    ANTENNADIFFAREA 0.434700 ;
    PORT
      LAYER met2 ;
        RECT 496.430 596.000 496.710 600.000 ;
    END
  END input_data[205]
  PIN input_data[206]
    DIRECTION INPUT ;
    USE SIGNAL ;
    ANTENNAGATEAREA 0.196500 ;
    ANTENNADIFFAREA 0.434700 ;
    PORT
      LAYER met2 ;
        RECT 498.730 596.000 499.010 600.000 ;
    END
  END input_data[206]
  PIN input_data[207]
    DIRECTION INPUT ;
    USE SIGNAL ;
    PORT
      LAYER met2 ;
        RECT 501.030 596.000 501.310 600.000 ;
    END
  END input_data[207]
  PIN input_data[208]
    DIRECTION INPUT ;
    USE SIGNAL ;
    PORT
      LAYER met2 ;
        RECT 503.330 596.000 503.610 600.000 ;
    END
  END input_data[208]
  PIN input_data[209]
    DIRECTION INPUT ;
    USE SIGNAL ;
    PORT
      LAYER met2 ;
        RECT 505.630 596.000 505.910 600.000 ;
    END
  END input_data[209]
  PIN input_data[20]
    DIRECTION INPUT ;
    USE SIGNAL ;
    ANTENNAGATEAREA 0.426000 ;
    ANTENNADIFFAREA 0.434700 ;
    PORT
      LAYER met2 ;
        RECT 70.930 596.000 71.210 600.000 ;
    END
  END input_data[20]
  PIN input_data[210]
    DIRECTION INPUT ;
    USE SIGNAL ;
    PORT
      LAYER met2 ;
        RECT 507.930 596.000 508.210 600.000 ;
    END
  END input_data[210]
  PIN input_data[211]
    DIRECTION INPUT ;
    USE SIGNAL ;
    PORT
      LAYER met2 ;
        RECT 510.230 596.000 510.510 600.000 ;
    END
  END input_data[211]
  PIN input_data[212]
    DIRECTION INPUT ;
    USE SIGNAL ;
    PORT
      LAYER met2 ;
        RECT 512.530 596.000 512.810 600.000 ;
    END
  END input_data[212]
  PIN input_data[213]
    DIRECTION INPUT ;
    USE SIGNAL ;
    PORT
      LAYER met2 ;
        RECT 514.830 596.000 515.110 600.000 ;
    END
  END input_data[213]
  PIN input_data[214]
    DIRECTION INPUT ;
    USE SIGNAL ;
    PORT
      LAYER met2 ;
        RECT 517.130 596.000 517.410 600.000 ;
    END
  END input_data[214]
  PIN input_data[215]
    DIRECTION INPUT ;
    USE SIGNAL ;
    PORT
      LAYER met2 ;
        RECT 519.430 596.000 519.710 600.000 ;
    END
  END input_data[215]
  PIN input_data[216]
    DIRECTION INPUT ;
    USE SIGNAL ;
    PORT
      LAYER met2 ;
        RECT 521.730 596.000 522.010 600.000 ;
    END
  END input_data[216]
  PIN input_data[217]
    DIRECTION INPUT ;
    USE SIGNAL ;
    PORT
      LAYER met2 ;
        RECT 524.030 596.000 524.310 600.000 ;
    END
  END input_data[217]
  PIN input_data[218]
    DIRECTION INPUT ;
    USE SIGNAL ;
    PORT
      LAYER met2 ;
        RECT 526.330 596.000 526.610 600.000 ;
    END
  END input_data[218]
  PIN input_data[219]
    DIRECTION INPUT ;
    USE SIGNAL ;
    PORT
      LAYER met2 ;
        RECT 528.630 596.000 528.910 600.000 ;
    END
  END input_data[219]
  PIN input_data[21]
    DIRECTION INPUT ;
    USE SIGNAL ;
    ANTENNAGATEAREA 0.196500 ;
    ANTENNADIFFAREA 0.434700 ;
    PORT
      LAYER met2 ;
        RECT 73.230 596.000 73.510 600.000 ;
    END
  END input_data[21]
  PIN input_data[220]
    DIRECTION INPUT ;
    USE SIGNAL ;
    PORT
      LAYER met2 ;
        RECT 530.930 596.000 531.210 600.000 ;
    END
  END input_data[220]
  PIN input_data[221]
    DIRECTION INPUT ;
    USE SIGNAL ;
    PORT
      LAYER met2 ;
        RECT 533.230 596.000 533.510 600.000 ;
    END
  END input_data[221]
  PIN input_data[222]
    DIRECTION INPUT ;
    USE SIGNAL ;
    PORT
      LAYER met2 ;
        RECT 535.530 596.000 535.810 600.000 ;
    END
  END input_data[222]
  PIN input_data[223]
    DIRECTION INPUT ;
    USE SIGNAL ;
    PORT
      LAYER met2 ;
        RECT 537.830 596.000 538.110 600.000 ;
    END
  END input_data[223]
  PIN input_data[224]
    DIRECTION INPUT ;
    USE SIGNAL ;
    ANTENNAGATEAREA 0.213000 ;
    ANTENNADIFFAREA 0.434700 ;
    PORT
      LAYER met2 ;
        RECT 540.130 596.000 540.410 600.000 ;
    END
  END input_data[224]
  PIN input_data[225]
    DIRECTION INPUT ;
    USE SIGNAL ;
    ANTENNAGATEAREA 0.247500 ;
    ANTENNADIFFAREA 0.434700 ;
    PORT
      LAYER met2 ;
        RECT 542.430 596.000 542.710 600.000 ;
    END
  END input_data[225]
  PIN input_data[226]
    DIRECTION INPUT ;
    USE SIGNAL ;
    ANTENNAGATEAREA 0.247500 ;
    ANTENNADIFFAREA 0.434700 ;
    PORT
      LAYER met2 ;
        RECT 544.730 596.000 545.010 600.000 ;
    END
  END input_data[226]
  PIN input_data[227]
    DIRECTION INPUT ;
    USE SIGNAL ;
    ANTENNAGATEAREA 0.213000 ;
    ANTENNADIFFAREA 0.434700 ;
    PORT
      LAYER met2 ;
        RECT 547.030 596.000 547.310 600.000 ;
    END
  END input_data[227]
  PIN input_data[228]
    DIRECTION INPUT ;
    USE SIGNAL ;
    ANTENNAGATEAREA 0.213000 ;
    ANTENNADIFFAREA 0.434700 ;
    PORT
      LAYER met2 ;
        RECT 549.330 596.000 549.610 600.000 ;
    END
  END input_data[228]
  PIN input_data[229]
    DIRECTION INPUT ;
    USE SIGNAL ;
    ANTENNAGATEAREA 0.213000 ;
    ANTENNADIFFAREA 0.434700 ;
    PORT
      LAYER met2 ;
        RECT 551.630 596.000 551.910 600.000 ;
    END
  END input_data[229]
  PIN input_data[22]
    DIRECTION INPUT ;
    USE SIGNAL ;
    ANTENNAGATEAREA 0.247500 ;
    ANTENNADIFFAREA 0.434700 ;
    PORT
      LAYER met2 ;
        RECT 75.530 596.000 75.810 600.000 ;
    END
  END input_data[22]
  PIN input_data[230]
    DIRECTION INPUT ;
    USE SIGNAL ;
    ANTENNAGATEAREA 0.213000 ;
    ANTENNADIFFAREA 0.434700 ;
    PORT
      LAYER met2 ;
        RECT 553.930 596.000 554.210 600.000 ;
    END
  END input_data[230]
  PIN input_data[231]
    DIRECTION INPUT ;
    USE SIGNAL ;
    ANTENNAGATEAREA 0.213000 ;
    ANTENNADIFFAREA 0.434700 ;
    PORT
      LAYER met2 ;
        RECT 556.230 596.000 556.510 600.000 ;
    END
  END input_data[231]
  PIN input_data[232]
    DIRECTION INPUT ;
    USE SIGNAL ;
    ANTENNAGATEAREA 0.213000 ;
    ANTENNADIFFAREA 0.434700 ;
    PORT
      LAYER met2 ;
        RECT 558.530 596.000 558.810 600.000 ;
    END
  END input_data[232]
  PIN input_data[233]
    DIRECTION INPUT ;
    USE SIGNAL ;
    ANTENNAGATEAREA 0.126000 ;
    ANTENNADIFFAREA 0.434700 ;
    PORT
      LAYER met2 ;
        RECT 560.830 596.000 561.110 600.000 ;
    END
  END input_data[233]
  PIN input_data[234]
    DIRECTION INPUT ;
    USE SIGNAL ;
    ANTENNAGATEAREA 0.126000 ;
    ANTENNADIFFAREA 0.434700 ;
    PORT
      LAYER met2 ;
        RECT 563.130 596.000 563.410 600.000 ;
    END
  END input_data[234]
  PIN input_data[235]
    DIRECTION INPUT ;
    USE SIGNAL ;
    ANTENNAGATEAREA 0.196500 ;
    ANTENNADIFFAREA 0.434700 ;
    PORT
      LAYER met2 ;
        RECT 565.430 596.000 565.710 600.000 ;
    END
  END input_data[235]
  PIN input_data[236]
    DIRECTION INPUT ;
    USE SIGNAL ;
    ANTENNAGATEAREA 0.196500 ;
    ANTENNADIFFAREA 0.434700 ;
    PORT
      LAYER met2 ;
        RECT 567.730 596.000 568.010 600.000 ;
    END
  END input_data[236]
  PIN input_data[237]
    DIRECTION INPUT ;
    USE SIGNAL ;
    ANTENNAGATEAREA 0.196500 ;
    ANTENNADIFFAREA 0.434700 ;
    PORT
      LAYER met2 ;
        RECT 570.030 596.000 570.310 600.000 ;
    END
  END input_data[237]
  PIN input_data[238]
    DIRECTION INPUT ;
    USE SIGNAL ;
    PORT
      LAYER met2 ;
        RECT 572.330 596.000 572.610 600.000 ;
    END
  END input_data[238]
  PIN input_data[239]
    DIRECTION INPUT ;
    USE SIGNAL ;
    PORT
      LAYER met2 ;
        RECT 574.630 596.000 574.910 600.000 ;
    END
  END input_data[239]
  PIN input_data[23]
    DIRECTION INPUT ;
    USE SIGNAL ;
    ANTENNAGATEAREA 0.247500 ;
    ANTENNADIFFAREA 0.434700 ;
    PORT
      LAYER met2 ;
        RECT 77.830 596.000 78.110 600.000 ;
    END
  END input_data[23]
  PIN input_data[24]
    DIRECTION INPUT ;
    USE SIGNAL ;
    ANTENNAGATEAREA 0.196500 ;
    ANTENNADIFFAREA 0.434700 ;
    PORT
      LAYER met2 ;
        RECT 80.130 596.000 80.410 600.000 ;
    END
  END input_data[24]
  PIN input_data[25]
    DIRECTION INPUT ;
    USE SIGNAL ;
    ANTENNAGATEAREA 0.213000 ;
    ANTENNADIFFAREA 0.434700 ;
    PORT
      LAYER met2 ;
        RECT 82.430 596.000 82.710 600.000 ;
    END
  END input_data[25]
  PIN input_data[26]
    DIRECTION INPUT ;
    USE SIGNAL ;
    ANTENNAGATEAREA 0.247500 ;
    ANTENNADIFFAREA 0.434700 ;
    PORT
      LAYER met2 ;
        RECT 84.730 596.000 85.010 600.000 ;
    END
  END input_data[26]
  PIN input_data[27]
    DIRECTION INPUT ;
    USE SIGNAL ;
    ANTENNAGATEAREA 0.426000 ;
    ANTENNADIFFAREA 0.434700 ;
    PORT
      LAYER met2 ;
        RECT 87.030 596.000 87.310 600.000 ;
    END
  END input_data[27]
  PIN input_data[28]
    DIRECTION INPUT ;
    USE SIGNAL ;
    ANTENNAGATEAREA 0.196500 ;
    ANTENNADIFFAREA 0.434700 ;
    PORT
      LAYER met2 ;
        RECT 89.330 596.000 89.610 600.000 ;
    END
  END input_data[28]
  PIN input_data[29]
    DIRECTION INPUT ;
    USE SIGNAL ;
    ANTENNAGATEAREA 0.426000 ;
    ANTENNADIFFAREA 0.434700 ;
    PORT
      LAYER met2 ;
        RECT 91.630 596.000 91.910 600.000 ;
    END
  END input_data[29]
  PIN input_data[2]
    DIRECTION INPUT ;
    USE SIGNAL ;
    ANTENNAGATEAREA 0.213000 ;
    ANTENNADIFFAREA 0.434700 ;
    PORT
      LAYER met2 ;
        RECT 29.530 596.000 29.810 600.000 ;
    END
  END input_data[2]
  PIN input_data[30]
    DIRECTION INPUT ;
    USE SIGNAL ;
    ANTENNAGATEAREA 0.213000 ;
    ANTENNADIFFAREA 0.434700 ;
    PORT
      LAYER met2 ;
        RECT 93.930 596.000 94.210 600.000 ;
    END
  END input_data[30]
  PIN input_data[31]
    DIRECTION INPUT ;
    USE SIGNAL ;
    ANTENNAGATEAREA 0.213000 ;
    ANTENNADIFFAREA 0.434700 ;
    PORT
      LAYER met2 ;
        RECT 96.230 596.000 96.510 600.000 ;
    END
  END input_data[31]
  PIN input_data[32]
    DIRECTION INPUT ;
    USE SIGNAL ;
    ANTENNAGATEAREA 0.213000 ;
    ANTENNADIFFAREA 0.434700 ;
    PORT
      LAYER met2 ;
        RECT 98.530 596.000 98.810 600.000 ;
    END
  END input_data[32]
  PIN input_data[33]
    DIRECTION INPUT ;
    USE SIGNAL ;
    ANTENNAGATEAREA 0.159000 ;
    ANTENNADIFFAREA 0.434700 ;
    PORT
      LAYER met2 ;
        RECT 100.830 596.000 101.110 600.000 ;
    END
  END input_data[33]
  PIN input_data[34]
    DIRECTION INPUT ;
    USE SIGNAL ;
    ANTENNAGATEAREA 0.159000 ;
    ANTENNADIFFAREA 0.434700 ;
    PORT
      LAYER met2 ;
        RECT 103.130 596.000 103.410 600.000 ;
    END
  END input_data[34]
  PIN input_data[35]
    DIRECTION INPUT ;
    USE SIGNAL ;
    ANTENNAGATEAREA 0.159000 ;
    ANTENNADIFFAREA 0.434700 ;
    PORT
      LAYER met2 ;
        RECT 105.430 596.000 105.710 600.000 ;
    END
  END input_data[35]
  PIN input_data[36]
    DIRECTION INPUT ;
    USE SIGNAL ;
    ANTENNAGATEAREA 0.213000 ;
    ANTENNADIFFAREA 0.434700 ;
    PORT
      LAYER met2 ;
        RECT 107.730 596.000 108.010 600.000 ;
    END
  END input_data[36]
  PIN input_data[37]
    DIRECTION INPUT ;
    USE SIGNAL ;
    ANTENNAGATEAREA 0.213000 ;
    ANTENNADIFFAREA 0.434700 ;
    PORT
      LAYER met2 ;
        RECT 110.030 596.000 110.310 600.000 ;
    END
  END input_data[37]
  PIN input_data[38]
    DIRECTION INPUT ;
    USE SIGNAL ;
    ANTENNAGATEAREA 0.213000 ;
    ANTENNADIFFAREA 0.434700 ;
    PORT
      LAYER met2 ;
        RECT 112.330 596.000 112.610 600.000 ;
    END
  END input_data[38]
  PIN input_data[39]
    DIRECTION INPUT ;
    USE SIGNAL ;
    ANTENNAGATEAREA 0.213000 ;
    ANTENNADIFFAREA 0.434700 ;
    PORT
      LAYER met2 ;
        RECT 114.630 596.000 114.910 600.000 ;
    END
  END input_data[39]
  PIN input_data[3]
    DIRECTION INPUT ;
    USE SIGNAL ;
    ANTENNAGATEAREA 0.213000 ;
    ANTENNADIFFAREA 0.434700 ;
    PORT
      LAYER met2 ;
        RECT 31.830 596.000 32.110 600.000 ;
    END
  END input_data[3]
  PIN input_data[40]
    DIRECTION INPUT ;
    USE SIGNAL ;
    ANTENNAGATEAREA 0.126000 ;
    ANTENNADIFFAREA 0.434700 ;
    PORT
      LAYER met2 ;
        RECT 116.930 596.000 117.210 600.000 ;
    END
  END input_data[40]
  PIN input_data[41]
    DIRECTION INPUT ;
    USE SIGNAL ;
    ANTENNAGATEAREA 0.213000 ;
    ANTENNADIFFAREA 0.434700 ;
    PORT
      LAYER met2 ;
        RECT 119.230 596.000 119.510 600.000 ;
    END
  END input_data[41]
  PIN input_data[42]
    DIRECTION INPUT ;
    USE SIGNAL ;
    ANTENNAGATEAREA 0.213000 ;
    ANTENNADIFFAREA 0.434700 ;
    PORT
      LAYER met2 ;
        RECT 121.530 596.000 121.810 600.000 ;
    END
  END input_data[42]
  PIN input_data[43]
    DIRECTION INPUT ;
    USE SIGNAL ;
    ANTENNAGATEAREA 0.213000 ;
    ANTENNADIFFAREA 0.434700 ;
    PORT
      LAYER met2 ;
        RECT 123.830 596.000 124.110 600.000 ;
    END
  END input_data[43]
  PIN input_data[44]
    DIRECTION INPUT ;
    USE SIGNAL ;
    ANTENNAGATEAREA 0.247500 ;
    ANTENNADIFFAREA 0.434700 ;
    PORT
      LAYER met2 ;
        RECT 126.130 596.000 126.410 600.000 ;
    END
  END input_data[44]
  PIN input_data[45]
    DIRECTION INPUT ;
    USE SIGNAL ;
    ANTENNAGATEAREA 0.213000 ;
    ANTENNADIFFAREA 0.434700 ;
    PORT
      LAYER met2 ;
        RECT 128.430 596.000 128.710 600.000 ;
    END
  END input_data[45]
  PIN input_data[46]
    DIRECTION INPUT ;
    USE SIGNAL ;
    ANTENNAGATEAREA 0.196500 ;
    ANTENNADIFFAREA 0.434700 ;
    PORT
      LAYER met2 ;
        RECT 130.730 596.000 131.010 600.000 ;
    END
  END input_data[46]
  PIN input_data[47]
    DIRECTION INPUT ;
    USE SIGNAL ;
    ANTENNAGATEAREA 0.196500 ;
    ANTENNADIFFAREA 0.434700 ;
    PORT
      LAYER met2 ;
        RECT 133.030 596.000 133.310 600.000 ;
    END
  END input_data[47]
  PIN input_data[48]
    DIRECTION INPUT ;
    USE SIGNAL ;
    ANTENNAGATEAREA 0.213000 ;
    ANTENNADIFFAREA 0.434700 ;
    PORT
      LAYER met2 ;
        RECT 135.330 596.000 135.610 600.000 ;
    END
  END input_data[48]
  PIN input_data[49]
    DIRECTION INPUT ;
    USE SIGNAL ;
    ANTENNAGATEAREA 0.213000 ;
    ANTENNADIFFAREA 0.434700 ;
    PORT
      LAYER met2 ;
        RECT 137.630 596.000 137.910 600.000 ;
    END
  END input_data[49]
  PIN input_data[4]
    DIRECTION INPUT ;
    USE SIGNAL ;
    ANTENNAGATEAREA 0.159000 ;
    ANTENNADIFFAREA 0.434700 ;
    PORT
      LAYER met2 ;
        RECT 34.130 596.000 34.410 600.000 ;
    END
  END input_data[4]
  PIN input_data[50]
    DIRECTION INPUT ;
    USE SIGNAL ;
    ANTENNAGATEAREA 0.213000 ;
    ANTENNADIFFAREA 0.434700 ;
    PORT
      LAYER met2 ;
        RECT 139.930 596.000 140.210 600.000 ;
    END
  END input_data[50]
  PIN input_data[51]
    DIRECTION INPUT ;
    USE SIGNAL ;
    ANTENNAGATEAREA 0.213000 ;
    ANTENNADIFFAREA 0.434700 ;
    PORT
      LAYER met2 ;
        RECT 142.230 596.000 142.510 600.000 ;
    END
  END input_data[51]
  PIN input_data[52]
    DIRECTION INPUT ;
    USE SIGNAL ;
    ANTENNAGATEAREA 0.213000 ;
    ANTENNADIFFAREA 0.434700 ;
    PORT
      LAYER met2 ;
        RECT 144.530 596.000 144.810 600.000 ;
    END
  END input_data[52]
  PIN input_data[53]
    DIRECTION INPUT ;
    USE SIGNAL ;
    ANTENNAGATEAREA 0.213000 ;
    ANTENNADIFFAREA 0.434700 ;
    PORT
      LAYER met2 ;
        RECT 146.830 596.000 147.110 600.000 ;
    END
  END input_data[53]
  PIN input_data[54]
    DIRECTION INPUT ;
    USE SIGNAL ;
    ANTENNAGATEAREA 0.213000 ;
    ANTENNADIFFAREA 0.434700 ;
    PORT
      LAYER met2 ;
        RECT 149.130 596.000 149.410 600.000 ;
    END
  END input_data[54]
  PIN input_data[55]
    DIRECTION INPUT ;
    USE SIGNAL ;
    ANTENNAGATEAREA 0.159000 ;
    ANTENNADIFFAREA 0.434700 ;
    PORT
      LAYER met2 ;
        RECT 151.430 596.000 151.710 600.000 ;
    END
  END input_data[55]
  PIN input_data[56]
    DIRECTION INPUT ;
    USE SIGNAL ;
    ANTENNAGATEAREA 0.159000 ;
    ANTENNADIFFAREA 0.434700 ;
    PORT
      LAYER met2 ;
        RECT 153.730 596.000 154.010 600.000 ;
    END
  END input_data[56]
  PIN input_data[57]
    DIRECTION INPUT ;
    USE SIGNAL ;
    ANTENNAGATEAREA 0.213000 ;
    ANTENNADIFFAREA 0.434700 ;
    PORT
      LAYER met2 ;
        RECT 156.030 596.000 156.310 600.000 ;
    END
  END input_data[57]
  PIN input_data[58]
    DIRECTION INPUT ;
    USE SIGNAL ;
    ANTENNAGATEAREA 0.213000 ;
    ANTENNADIFFAREA 0.434700 ;
    PORT
      LAYER met2 ;
        RECT 158.330 596.000 158.610 600.000 ;
    END
  END input_data[58]
  PIN input_data[59]
    DIRECTION INPUT ;
    USE SIGNAL ;
    ANTENNAGATEAREA 0.247500 ;
    ANTENNADIFFAREA 0.434700 ;
    PORT
      LAYER met2 ;
        RECT 160.630 596.000 160.910 600.000 ;
    END
  END input_data[59]
  PIN input_data[5]
    DIRECTION INPUT ;
    USE SIGNAL ;
    ANTENNAGATEAREA 0.159000 ;
    ANTENNADIFFAREA 0.434700 ;
    PORT
      LAYER met2 ;
        RECT 36.430 596.000 36.710 600.000 ;
    END
  END input_data[5]
  PIN input_data[60]
    DIRECTION INPUT ;
    USE SIGNAL ;
    ANTENNAGATEAREA 0.213000 ;
    ANTENNADIFFAREA 0.434700 ;
    PORT
      LAYER met2 ;
        RECT 162.930 596.000 163.210 600.000 ;
    END
  END input_data[60]
  PIN input_data[61]
    DIRECTION INPUT ;
    USE SIGNAL ;
    ANTENNAGATEAREA 0.159000 ;
    ANTENNADIFFAREA 0.434700 ;
    PORT
      LAYER met2 ;
        RECT 165.230 596.000 165.510 600.000 ;
    END
  END input_data[61]
  PIN input_data[62]
    DIRECTION INPUT ;
    USE SIGNAL ;
    ANTENNAGATEAREA 0.213000 ;
    ANTENNADIFFAREA 0.434700 ;
    PORT
      LAYER met2 ;
        RECT 167.530 596.000 167.810 600.000 ;
    END
  END input_data[62]
  PIN input_data[63]
    DIRECTION INPUT ;
    USE SIGNAL ;
    PORT
      LAYER met2 ;
        RECT 169.830 596.000 170.110 600.000 ;
    END
  END input_data[63]
  PIN input_data[64]
    DIRECTION INPUT ;
    USE SIGNAL ;
    ANTENNAGATEAREA 0.196500 ;
    ANTENNADIFFAREA 0.434700 ;
    PORT
      LAYER met2 ;
        RECT 172.130 596.000 172.410 600.000 ;
    END
  END input_data[64]
  PIN input_data[65]
    DIRECTION INPUT ;
    USE SIGNAL ;
    ANTENNAGATEAREA 0.213000 ;
    ANTENNADIFFAREA 0.434700 ;
    PORT
      LAYER met2 ;
        RECT 174.430 596.000 174.710 600.000 ;
    END
  END input_data[65]
  PIN input_data[66]
    DIRECTION INPUT ;
    USE SIGNAL ;
    ANTENNAGATEAREA 0.196500 ;
    ANTENNADIFFAREA 0.434700 ;
    PORT
      LAYER met2 ;
        RECT 176.730 596.000 177.010 600.000 ;
    END
  END input_data[66]
  PIN input_data[67]
    DIRECTION INPUT ;
    USE SIGNAL ;
    ANTENNAGATEAREA 0.196500 ;
    ANTENNADIFFAREA 0.434700 ;
    PORT
      LAYER met2 ;
        RECT 179.030 596.000 179.310 600.000 ;
    END
  END input_data[67]
  PIN input_data[68]
    DIRECTION INPUT ;
    USE SIGNAL ;
    ANTENNAGATEAREA 0.213000 ;
    ANTENNADIFFAREA 0.434700 ;
    PORT
      LAYER met2 ;
        RECT 181.330 596.000 181.610 600.000 ;
    END
  END input_data[68]
  PIN input_data[69]
    DIRECTION INPUT ;
    USE SIGNAL ;
    ANTENNAGATEAREA 0.196500 ;
    ANTENNADIFFAREA 0.434700 ;
    PORT
      LAYER met2 ;
        RECT 183.630 596.000 183.910 600.000 ;
    END
  END input_data[69]
  PIN input_data[6]
    DIRECTION INPUT ;
    USE SIGNAL ;
    ANTENNAGATEAREA 0.159000 ;
    ANTENNADIFFAREA 0.434700 ;
    PORT
      LAYER met2 ;
        RECT 38.730 596.000 39.010 600.000 ;
    END
  END input_data[6]
  PIN input_data[70]
    DIRECTION INPUT ;
    USE SIGNAL ;
    ANTENNAGATEAREA 0.196500 ;
    ANTENNADIFFAREA 0.434700 ;
    PORT
      LAYER met2 ;
        RECT 185.930 596.000 186.210 600.000 ;
    END
  END input_data[70]
  PIN input_data[71]
    DIRECTION INPUT ;
    USE SIGNAL ;
    ANTENNAGATEAREA 0.196500 ;
    ANTENNADIFFAREA 0.434700 ;
    PORT
      LAYER met2 ;
        RECT 188.230 596.000 188.510 600.000 ;
    END
  END input_data[71]
  PIN input_data[72]
    DIRECTION INPUT ;
    USE SIGNAL ;
    ANTENNAGATEAREA 0.196500 ;
    ANTENNADIFFAREA 0.434700 ;
    PORT
      LAYER met2 ;
        RECT 190.530 596.000 190.810 600.000 ;
    END
  END input_data[72]
  PIN input_data[73]
    DIRECTION INPUT ;
    USE SIGNAL ;
    ANTENNAGATEAREA 0.196500 ;
    ANTENNADIFFAREA 0.434700 ;
    PORT
      LAYER met2 ;
        RECT 192.830 596.000 193.110 600.000 ;
    END
  END input_data[73]
  PIN input_data[74]
    DIRECTION INPUT ;
    USE SIGNAL ;
    ANTENNAGATEAREA 0.213000 ;
    ANTENNADIFFAREA 0.434700 ;
    PORT
      LAYER met2 ;
        RECT 195.130 596.000 195.410 600.000 ;
    END
  END input_data[74]
  PIN input_data[75]
    DIRECTION INPUT ;
    USE SIGNAL ;
    ANTENNAGATEAREA 0.196500 ;
    ANTENNADIFFAREA 0.434700 ;
    PORT
      LAYER met2 ;
        RECT 197.430 596.000 197.710 600.000 ;
    END
  END input_data[75]
  PIN input_data[76]
    DIRECTION INPUT ;
    USE SIGNAL ;
    ANTENNAGATEAREA 0.196500 ;
    ANTENNADIFFAREA 0.434700 ;
    PORT
      LAYER met2 ;
        RECT 199.730 596.000 200.010 600.000 ;
    END
  END input_data[76]
  PIN input_data[77]
    DIRECTION INPUT ;
    USE SIGNAL ;
    ANTENNAGATEAREA 0.213000 ;
    ANTENNADIFFAREA 0.434700 ;
    PORT
      LAYER met2 ;
        RECT 202.030 596.000 202.310 600.000 ;
    END
  END input_data[77]
  PIN input_data[78]
    DIRECTION INPUT ;
    USE SIGNAL ;
    ANTENNAGATEAREA 0.196500 ;
    ANTENNADIFFAREA 0.434700 ;
    PORT
      LAYER met2 ;
        RECT 204.330 596.000 204.610 600.000 ;
    END
  END input_data[78]
  PIN input_data[79]
    DIRECTION INPUT ;
    USE SIGNAL ;
    PORT
      LAYER met2 ;
        RECT 206.630 596.000 206.910 600.000 ;
    END
  END input_data[79]
  PIN input_data[7]
    DIRECTION INPUT ;
    USE SIGNAL ;
    ANTENNAGATEAREA 0.159000 ;
    ANTENNADIFFAREA 0.434700 ;
    PORT
      LAYER met2 ;
        RECT 41.030 596.000 41.310 600.000 ;
    END
  END input_data[7]
  PIN input_data[80]
    DIRECTION INPUT ;
    USE SIGNAL ;
    ANTENNAGATEAREA 0.159000 ;
    ANTENNADIFFAREA 0.434700 ;
    PORT
      LAYER met2 ;
        RECT 208.930 596.000 209.210 600.000 ;
    END
  END input_data[80]
  PIN input_data[81]
    DIRECTION INPUT ;
    USE SIGNAL ;
    ANTENNAGATEAREA 0.159000 ;
    ANTENNADIFFAREA 0.434700 ;
    PORT
      LAYER met2 ;
        RECT 211.230 596.000 211.510 600.000 ;
    END
  END input_data[81]
  PIN input_data[82]
    DIRECTION INPUT ;
    USE SIGNAL ;
    ANTENNAGATEAREA 0.247500 ;
    ANTENNADIFFAREA 0.434700 ;
    PORT
      LAYER met2 ;
        RECT 213.530 596.000 213.810 600.000 ;
    END
  END input_data[82]
  PIN input_data[83]
    DIRECTION INPUT ;
    USE SIGNAL ;
    ANTENNAGATEAREA 0.213000 ;
    ANTENNADIFFAREA 0.434700 ;
    PORT
      LAYER met2 ;
        RECT 215.830 596.000 216.110 600.000 ;
    END
  END input_data[83]
  PIN input_data[84]
    DIRECTION INPUT ;
    USE SIGNAL ;
    ANTENNAGATEAREA 0.247500 ;
    ANTENNADIFFAREA 0.434700 ;
    PORT
      LAYER met2 ;
        RECT 218.130 596.000 218.410 600.000 ;
    END
  END input_data[84]
  PIN input_data[85]
    DIRECTION INPUT ;
    USE SIGNAL ;
    ANTENNAGATEAREA 0.213000 ;
    ANTENNADIFFAREA 0.434700 ;
    PORT
      LAYER met2 ;
        RECT 220.430 596.000 220.710 600.000 ;
    END
  END input_data[85]
  PIN input_data[86]
    DIRECTION INPUT ;
    USE SIGNAL ;
    ANTENNAGATEAREA 0.247500 ;
    ANTENNADIFFAREA 0.434700 ;
    PORT
      LAYER met2 ;
        RECT 222.730 596.000 223.010 600.000 ;
    END
  END input_data[86]
  PIN input_data[87]
    DIRECTION INPUT ;
    USE SIGNAL ;
    ANTENNAGATEAREA 0.247500 ;
    ANTENNADIFFAREA 0.434700 ;
    PORT
      LAYER met2 ;
        RECT 225.030 596.000 225.310 600.000 ;
    END
  END input_data[87]
  PIN input_data[88]
    DIRECTION INPUT ;
    USE SIGNAL ;
    ANTENNAGATEAREA 0.247500 ;
    ANTENNADIFFAREA 0.434700 ;
    PORT
      LAYER met2 ;
        RECT 227.330 596.000 227.610 600.000 ;
    END
  END input_data[88]
  PIN input_data[89]
    DIRECTION INPUT ;
    USE SIGNAL ;
    ANTENNAGATEAREA 0.213000 ;
    ANTENNADIFFAREA 0.434700 ;
    PORT
      LAYER met2 ;
        RECT 229.630 596.000 229.910 600.000 ;
    END
  END input_data[89]
  PIN input_data[8]
    DIRECTION INPUT ;
    USE SIGNAL ;
    ANTENNAGATEAREA 0.159000 ;
    ANTENNADIFFAREA 0.434700 ;
    PORT
      LAYER met2 ;
        RECT 43.330 596.000 43.610 600.000 ;
    END
  END input_data[8]
  PIN input_data[90]
    DIRECTION INPUT ;
    USE SIGNAL ;
    ANTENNAGATEAREA 0.213000 ;
    ANTENNADIFFAREA 0.434700 ;
    PORT
      LAYER met2 ;
        RECT 231.930 596.000 232.210 600.000 ;
    END
  END input_data[90]
  PIN input_data[91]
    DIRECTION INPUT ;
    USE SIGNAL ;
    ANTENNAGATEAREA 0.247500 ;
    ANTENNADIFFAREA 0.434700 ;
    PORT
      LAYER met2 ;
        RECT 234.230 596.000 234.510 600.000 ;
    END
  END input_data[91]
  PIN input_data[92]
    DIRECTION INPUT ;
    USE SIGNAL ;
    ANTENNAGATEAREA 0.247500 ;
    ANTENNADIFFAREA 0.434700 ;
    PORT
      LAYER met2 ;
        RECT 236.530 596.000 236.810 600.000 ;
    END
  END input_data[92]
  PIN input_data[93]
    DIRECTION INPUT ;
    USE SIGNAL ;
    ANTENNAGATEAREA 0.247500 ;
    ANTENNADIFFAREA 0.434700 ;
    PORT
      LAYER met2 ;
        RECT 238.830 596.000 239.110 600.000 ;
    END
  END input_data[93]
  PIN input_data[94]
    DIRECTION INPUT ;
    USE SIGNAL ;
    ANTENNAGATEAREA 0.213000 ;
    ANTENNADIFFAREA 0.434700 ;
    PORT
      LAYER met2 ;
        RECT 241.130 596.000 241.410 600.000 ;
    END
  END input_data[94]
  PIN input_data[95]
    DIRECTION INPUT ;
    USE SIGNAL ;
    ANTENNAGATEAREA 0.126000 ;
    ANTENNADIFFAREA 0.434700 ;
    PORT
      LAYER met2 ;
        RECT 243.430 596.000 243.710 600.000 ;
    END
  END input_data[95]
  PIN input_data[96]
    DIRECTION INPUT ;
    USE SIGNAL ;
    ANTENNAGATEAREA 0.196500 ;
    ANTENNADIFFAREA 0.434700 ;
    PORT
      LAYER met2 ;
        RECT 245.730 596.000 246.010 600.000 ;
    END
  END input_data[96]
  PIN input_data[97]
    DIRECTION INPUT ;
    USE SIGNAL ;
    ANTENNAGATEAREA 0.213000 ;
    ANTENNADIFFAREA 0.434700 ;
    PORT
      LAYER met2 ;
        RECT 248.030 596.000 248.310 600.000 ;
    END
  END input_data[97]
  PIN input_data[98]
    DIRECTION INPUT ;
    USE SIGNAL ;
    ANTENNAGATEAREA 0.196500 ;
    ANTENNADIFFAREA 0.434700 ;
    PORT
      LAYER met2 ;
        RECT 250.330 596.000 250.610 600.000 ;
    END
  END input_data[98]
  PIN input_data[99]
    DIRECTION INPUT ;
    USE SIGNAL ;
    ANTENNAGATEAREA 0.196500 ;
    ANTENNADIFFAREA 0.434700 ;
    PORT
      LAYER met2 ;
        RECT 252.630 596.000 252.910 600.000 ;
    END
  END input_data[99]
  PIN input_data[9]
    DIRECTION INPUT ;
    USE SIGNAL ;
    ANTENNAGATEAREA 0.213000 ;
    ANTENNADIFFAREA 0.434700 ;
    PORT
      LAYER met2 ;
        RECT 45.630 596.000 45.910 600.000 ;
    END
  END input_data[9]
  PIN output_high[0]
    DIRECTION OUTPUT ;
    USE SIGNAL ;
    ANTENNADIFFAREA 0.445500 ;
    PORT
      LAYER met3 ;
        RECT 0.000 23.160 4.000 23.760 ;
    END
  END output_high[0]
  PIN output_high[10]
    DIRECTION OUTPUT ;
    USE SIGNAL ;
    ANTENNADIFFAREA 0.445500 ;
    PORT
      LAYER met3 ;
        RECT 0.000 390.360 4.000 390.960 ;
    END
  END output_high[10]
  PIN output_high[11]
    DIRECTION OUTPUT ;
    USE SIGNAL ;
    ANTENNADIFFAREA 0.445500 ;
    PORT
      LAYER met3 ;
        RECT 0.000 427.080 4.000 427.680 ;
    END
  END output_high[11]
  PIN output_high[12]
    DIRECTION OUTPUT ;
    USE SIGNAL ;
    ANTENNADIFFAREA 0.445500 ;
    PORT
      LAYER met3 ;
        RECT 0.000 463.800 4.000 464.400 ;
    END
  END output_high[12]
  PIN output_high[13]
    DIRECTION OUTPUT ;
    USE SIGNAL ;
    ANTENNADIFFAREA 0.445500 ;
    PORT
      LAYER met3 ;
        RECT 0.000 500.520 4.000 501.120 ;
    END
  END output_high[13]
  PIN output_high[14]
    DIRECTION OUTPUT ;
    USE SIGNAL ;
    ANTENNADIFFAREA 0.445500 ;
    PORT
      LAYER met3 ;
        RECT 0.000 537.240 4.000 537.840 ;
    END
  END output_high[14]
  PIN output_high[15]
    DIRECTION OUTPUT ;
    USE SIGNAL ;
    ANTENNADIFFAREA 0.445500 ;
    PORT
      LAYER met3 ;
        RECT 0.000 573.960 4.000 574.560 ;
    END
  END output_high[15]
  PIN output_high[1]
    DIRECTION OUTPUT ;
    USE SIGNAL ;
    ANTENNADIFFAREA 0.445500 ;
    PORT
      LAYER met3 ;
        RECT 0.000 59.880 4.000 60.480 ;
    END
  END output_high[1]
  PIN output_high[2]
    DIRECTION OUTPUT ;
    USE SIGNAL ;
    ANTENNADIFFAREA 0.445500 ;
    PORT
      LAYER met3 ;
        RECT 0.000 96.600 4.000 97.200 ;
    END
  END output_high[2]
  PIN output_high[3]
    DIRECTION OUTPUT ;
    USE SIGNAL ;
    ANTENNADIFFAREA 0.445500 ;
    PORT
      LAYER met3 ;
        RECT 0.000 133.320 4.000 133.920 ;
    END
  END output_high[3]
  PIN output_high[4]
    DIRECTION OUTPUT ;
    USE SIGNAL ;
    ANTENNADIFFAREA 0.445500 ;
    PORT
      LAYER met3 ;
        RECT 0.000 170.040 4.000 170.640 ;
    END
  END output_high[4]
  PIN output_high[5]
    DIRECTION OUTPUT ;
    USE SIGNAL ;
    ANTENNADIFFAREA 0.445500 ;
    PORT
      LAYER met3 ;
        RECT 0.000 206.760 4.000 207.360 ;
    END
  END output_high[5]
  PIN output_high[6]
    DIRECTION OUTPUT ;
    USE SIGNAL ;
    ANTENNADIFFAREA 0.445500 ;
    PORT
      LAYER met3 ;
        RECT 0.000 243.480 4.000 244.080 ;
    END
  END output_high[6]
  PIN output_high[7]
    DIRECTION OUTPUT ;
    USE SIGNAL ;
    ANTENNADIFFAREA 0.445500 ;
    PORT
      LAYER met3 ;
        RECT 0.000 280.200 4.000 280.800 ;
    END
  END output_high[7]
  PIN output_high[8]
    DIRECTION OUTPUT ;
    USE SIGNAL ;
    ANTENNADIFFAREA 0.445500 ;
    PORT
      LAYER met3 ;
        RECT 0.000 316.920 4.000 317.520 ;
    END
  END output_high[8]
  PIN output_high[9]
    DIRECTION OUTPUT ;
    USE SIGNAL ;
    ANTENNADIFFAREA 0.445500 ;
    PORT
      LAYER met3 ;
        RECT 0.000 353.640 4.000 354.240 ;
    END
  END output_high[9]
  PIN tap[0]
    DIRECTION INPUT ;
    USE SIGNAL ;
    ANTENNAGATEAREA 0.159000 ;
    ANTENNADIFFAREA 0.434700 ;
    PORT
      LAYER met2 ;
        RECT 74.610 0.000 74.890 4.000 ;
    END
  END tap[0]
  PIN tap[1]
    DIRECTION INPUT ;
    USE SIGNAL ;
    ANTENNAGATEAREA 0.159000 ;
    ANTENNADIFFAREA 0.434700 ;
    PORT
      LAYER met2 ;
        RECT 224.570 0.000 224.850 4.000 ;
    END
  END tap[1]
  PIN tap[2]
    DIRECTION INPUT ;
    USE SIGNAL ;
    ANTENNAGATEAREA 0.247500 ;
    ANTENNADIFFAREA 0.434700 ;
    PORT
      LAYER met2 ;
        RECT 374.530 0.000 374.810 4.000 ;
    END
  END tap[2]
  PIN tap[3]
    DIRECTION INPUT ;
    USE SIGNAL ;
    ANTENNAGATEAREA 0.426000 ;
    ANTENNADIFFAREA 0.434700 ;
    PORT
      LAYER met2 ;
        RECT 524.490 0.000 524.770 4.000 ;
    END
  END tap[3]
  OBS
      LAYER li1 ;
        RECT 5.520 10.795 594.320 587.605 ;
      LAYER met1 ;
        RECT 4.670 10.640 594.320 587.760 ;
      LAYER met2 ;
        RECT 4.690 595.720 24.650 596.770 ;
        RECT 25.490 595.720 26.950 596.770 ;
        RECT 27.790 595.720 29.250 596.770 ;
        RECT 30.090 595.720 31.550 596.770 ;
        RECT 32.390 595.720 33.850 596.770 ;
        RECT 34.690 595.720 36.150 596.770 ;
        RECT 36.990 595.720 38.450 596.770 ;
        RECT 39.290 595.720 40.750 596.770 ;
        RECT 41.590 595.720 43.050 596.770 ;
        RECT 43.890 595.720 45.350 596.770 ;
        RECT 46.190 595.720 47.650 596.770 ;
        RECT 48.490 595.720 49.950 596.770 ;
        RECT 50.790 595.720 52.250 596.770 ;
        RECT 53.090 595.720 54.550 596.770 ;
        RECT 55.390 595.720 56.850 596.770 ;
        RECT 57.690 595.720 59.150 596.770 ;
        RECT 59.990 595.720 61.450 596.770 ;
        RECT 62.290 595.720 63.750 596.770 ;
        RECT 64.590 595.720 66.050 596.770 ;
        RECT 66.890 595.720 68.350 596.770 ;
        RECT 69.190 595.720 70.650 596.770 ;
        RECT 71.490 595.720 72.950 596.770 ;
        RECT 73.790 595.720 75.250 596.770 ;
        RECT 76.090 595.720 77.550 596.770 ;
        RECT 78.390 595.720 79.850 596.770 ;
        RECT 80.690 595.720 82.150 596.770 ;
        RECT 82.990 595.720 84.450 596.770 ;
        RECT 85.290 595.720 86.750 596.770 ;
        RECT 87.590 595.720 89.050 596.770 ;
        RECT 89.890 595.720 91.350 596.770 ;
        RECT 92.190 595.720 93.650 596.770 ;
        RECT 94.490 595.720 95.950 596.770 ;
        RECT 96.790 595.720 98.250 596.770 ;
        RECT 99.090 595.720 100.550 596.770 ;
        RECT 101.390 595.720 102.850 596.770 ;
        RECT 103.690 595.720 105.150 596.770 ;
        RECT 105.990 595.720 107.450 596.770 ;
        RECT 108.290 595.720 109.750 596.770 ;
        RECT 110.590 595.720 112.050 596.770 ;
        RECT 112.890 595.720 114.350 596.770 ;
        RECT 115.190 595.720 116.650 596.770 ;
        RECT 117.490 595.720 118.950 596.770 ;
        RECT 119.790 595.720 121.250 596.770 ;
        RECT 122.090 595.720 123.550 596.770 ;
        RECT 124.390 595.720 125.850 596.770 ;
        RECT 126.690 595.720 128.150 596.770 ;
        RECT 128.990 595.720 130.450 596.770 ;
        RECT 131.290 595.720 132.750 596.770 ;
        RECT 133.590 595.720 135.050 596.770 ;
        RECT 135.890 595.720 137.350 596.770 ;
        RECT 138.190 595.720 139.650 596.770 ;
        RECT 140.490 595.720 141.950 596.770 ;
        RECT 142.790 595.720 144.250 596.770 ;
        RECT 145.090 595.720 146.550 596.770 ;
        RECT 147.390 595.720 148.850 596.770 ;
        RECT 149.690 595.720 151.150 596.770 ;
        RECT 151.990 595.720 153.450 596.770 ;
        RECT 154.290 595.720 155.750 596.770 ;
        RECT 156.590 595.720 158.050 596.770 ;
        RECT 158.890 595.720 160.350 596.770 ;
        RECT 161.190 595.720 162.650 596.770 ;
        RECT 163.490 595.720 164.950 596.770 ;
        RECT 165.790 595.720 167.250 596.770 ;
        RECT 168.090 595.720 169.550 596.770 ;
        RECT 170.390 595.720 171.850 596.770 ;
        RECT 172.690 595.720 174.150 596.770 ;
        RECT 174.990 595.720 176.450 596.770 ;
        RECT 177.290 595.720 178.750 596.770 ;
        RECT 179.590 595.720 181.050 596.770 ;
        RECT 181.890 595.720 183.350 596.770 ;
        RECT 184.190 595.720 185.650 596.770 ;
        RECT 186.490 595.720 187.950 596.770 ;
        RECT 188.790 595.720 190.250 596.770 ;
        RECT 191.090 595.720 192.550 596.770 ;
        RECT 193.390 595.720 194.850 596.770 ;
        RECT 195.690 595.720 197.150 596.770 ;
        RECT 197.990 595.720 199.450 596.770 ;
        RECT 200.290 595.720 201.750 596.770 ;
        RECT 202.590 595.720 204.050 596.770 ;
        RECT 204.890 595.720 206.350 596.770 ;
        RECT 207.190 595.720 208.650 596.770 ;
        RECT 209.490 595.720 210.950 596.770 ;
        RECT 211.790 595.720 213.250 596.770 ;
        RECT 214.090 595.720 215.550 596.770 ;
        RECT 216.390 595.720 217.850 596.770 ;
        RECT 218.690 595.720 220.150 596.770 ;
        RECT 220.990 595.720 222.450 596.770 ;
        RECT 223.290 595.720 224.750 596.770 ;
        RECT 225.590 595.720 227.050 596.770 ;
        RECT 227.890 595.720 229.350 596.770 ;
        RECT 230.190 595.720 231.650 596.770 ;
        RECT 232.490 595.720 233.950 596.770 ;
        RECT 234.790 595.720 236.250 596.770 ;
        RECT 237.090 595.720 238.550 596.770 ;
        RECT 239.390 595.720 240.850 596.770 ;
        RECT 241.690 595.720 243.150 596.770 ;
        RECT 243.990 595.720 245.450 596.770 ;
        RECT 246.290 595.720 247.750 596.770 ;
        RECT 248.590 595.720 250.050 596.770 ;
        RECT 250.890 595.720 252.350 596.770 ;
        RECT 253.190 595.720 254.650 596.770 ;
        RECT 255.490 595.720 256.950 596.770 ;
        RECT 257.790 595.720 259.250 596.770 ;
        RECT 260.090 595.720 261.550 596.770 ;
        RECT 262.390 595.720 263.850 596.770 ;
        RECT 264.690 595.720 266.150 596.770 ;
        RECT 266.990 595.720 268.450 596.770 ;
        RECT 269.290 595.720 270.750 596.770 ;
        RECT 271.590 595.720 273.050 596.770 ;
        RECT 273.890 595.720 275.350 596.770 ;
        RECT 276.190 595.720 277.650 596.770 ;
        RECT 278.490 595.720 279.950 596.770 ;
        RECT 280.790 595.720 282.250 596.770 ;
        RECT 283.090 595.720 284.550 596.770 ;
        RECT 285.390 595.720 286.850 596.770 ;
        RECT 287.690 595.720 289.150 596.770 ;
        RECT 289.990 595.720 291.450 596.770 ;
        RECT 292.290 595.720 293.750 596.770 ;
        RECT 294.590 595.720 296.050 596.770 ;
        RECT 296.890 595.720 298.350 596.770 ;
        RECT 299.190 595.720 300.650 596.770 ;
        RECT 301.490 595.720 302.950 596.770 ;
        RECT 303.790 595.720 305.250 596.770 ;
        RECT 306.090 595.720 307.550 596.770 ;
        RECT 308.390 595.720 309.850 596.770 ;
        RECT 310.690 595.720 312.150 596.770 ;
        RECT 312.990 595.720 314.450 596.770 ;
        RECT 315.290 595.720 316.750 596.770 ;
        RECT 317.590 595.720 319.050 596.770 ;
        RECT 319.890 595.720 321.350 596.770 ;
        RECT 322.190 595.720 323.650 596.770 ;
        RECT 324.490 595.720 325.950 596.770 ;
        RECT 326.790 595.720 328.250 596.770 ;
        RECT 329.090 595.720 330.550 596.770 ;
        RECT 331.390 595.720 332.850 596.770 ;
        RECT 333.690 595.720 335.150 596.770 ;
        RECT 335.990 595.720 337.450 596.770 ;
        RECT 338.290 595.720 339.750 596.770 ;
        RECT 340.590 595.720 342.050 596.770 ;
        RECT 342.890 595.720 344.350 596.770 ;
        RECT 345.190 595.720 346.650 596.770 ;
        RECT 347.490 595.720 348.950 596.770 ;
        RECT 349.790 595.720 351.250 596.770 ;
        RECT 352.090 595.720 353.550 596.770 ;
        RECT 354.390 595.720 355.850 596.770 ;
        RECT 356.690 595.720 358.150 596.770 ;
        RECT 358.990 595.720 360.450 596.770 ;
        RECT 361.290 595.720 362.750 596.770 ;
        RECT 363.590 595.720 365.050 596.770 ;
        RECT 365.890 595.720 367.350 596.770 ;
        RECT 368.190 595.720 369.650 596.770 ;
        RECT 370.490 595.720 371.950 596.770 ;
        RECT 372.790 595.720 374.250 596.770 ;
        RECT 375.090 595.720 376.550 596.770 ;
        RECT 377.390 595.720 378.850 596.770 ;
        RECT 379.690 595.720 381.150 596.770 ;
        RECT 381.990 595.720 383.450 596.770 ;
        RECT 384.290 595.720 385.750 596.770 ;
        RECT 386.590 595.720 388.050 596.770 ;
        RECT 388.890 595.720 390.350 596.770 ;
        RECT 391.190 595.720 392.650 596.770 ;
        RECT 393.490 595.720 394.950 596.770 ;
        RECT 395.790 595.720 397.250 596.770 ;
        RECT 398.090 595.720 399.550 596.770 ;
        RECT 400.390 595.720 401.850 596.770 ;
        RECT 402.690 595.720 404.150 596.770 ;
        RECT 404.990 595.720 406.450 596.770 ;
        RECT 407.290 595.720 408.750 596.770 ;
        RECT 409.590 595.720 411.050 596.770 ;
        RECT 411.890 595.720 413.350 596.770 ;
        RECT 414.190 595.720 415.650 596.770 ;
        RECT 416.490 595.720 417.950 596.770 ;
        RECT 418.790 595.720 420.250 596.770 ;
        RECT 421.090 595.720 422.550 596.770 ;
        RECT 423.390 595.720 424.850 596.770 ;
        RECT 425.690 595.720 427.150 596.770 ;
        RECT 427.990 595.720 429.450 596.770 ;
        RECT 430.290 595.720 431.750 596.770 ;
        RECT 432.590 595.720 434.050 596.770 ;
        RECT 434.890 595.720 436.350 596.770 ;
        RECT 437.190 595.720 438.650 596.770 ;
        RECT 439.490 595.720 440.950 596.770 ;
        RECT 441.790 595.720 443.250 596.770 ;
        RECT 444.090 595.720 445.550 596.770 ;
        RECT 446.390 595.720 447.850 596.770 ;
        RECT 448.690 595.720 450.150 596.770 ;
        RECT 450.990 595.720 452.450 596.770 ;
        RECT 453.290 595.720 454.750 596.770 ;
        RECT 455.590 595.720 457.050 596.770 ;
        RECT 457.890 595.720 459.350 596.770 ;
        RECT 460.190 595.720 461.650 596.770 ;
        RECT 462.490 595.720 463.950 596.770 ;
        RECT 464.790 595.720 466.250 596.770 ;
        RECT 467.090 595.720 468.550 596.770 ;
        RECT 469.390 595.720 470.850 596.770 ;
        RECT 471.690 595.720 473.150 596.770 ;
        RECT 473.990 595.720 475.450 596.770 ;
        RECT 476.290 595.720 477.750 596.770 ;
        RECT 478.590 595.720 480.050 596.770 ;
        RECT 480.890 595.720 482.350 596.770 ;
        RECT 483.190 595.720 484.650 596.770 ;
        RECT 485.490 595.720 486.950 596.770 ;
        RECT 487.790 595.720 489.250 596.770 ;
        RECT 490.090 595.720 491.550 596.770 ;
        RECT 492.390 595.720 493.850 596.770 ;
        RECT 494.690 595.720 496.150 596.770 ;
        RECT 496.990 595.720 498.450 596.770 ;
        RECT 499.290 595.720 500.750 596.770 ;
        RECT 501.590 595.720 503.050 596.770 ;
        RECT 503.890 595.720 505.350 596.770 ;
        RECT 506.190 595.720 507.650 596.770 ;
        RECT 508.490 595.720 509.950 596.770 ;
        RECT 510.790 595.720 512.250 596.770 ;
        RECT 513.090 595.720 514.550 596.770 ;
        RECT 515.390 595.720 516.850 596.770 ;
        RECT 517.690 595.720 519.150 596.770 ;
        RECT 519.990 595.720 521.450 596.770 ;
        RECT 522.290 595.720 523.750 596.770 ;
        RECT 524.590 595.720 526.050 596.770 ;
        RECT 526.890 595.720 528.350 596.770 ;
        RECT 529.190 595.720 530.650 596.770 ;
        RECT 531.490 595.720 532.950 596.770 ;
        RECT 533.790 595.720 535.250 596.770 ;
        RECT 536.090 595.720 537.550 596.770 ;
        RECT 538.390 595.720 539.850 596.770 ;
        RECT 540.690 595.720 542.150 596.770 ;
        RECT 542.990 595.720 544.450 596.770 ;
        RECT 545.290 595.720 546.750 596.770 ;
        RECT 547.590 595.720 549.050 596.770 ;
        RECT 549.890 595.720 551.350 596.770 ;
        RECT 552.190 595.720 553.650 596.770 ;
        RECT 554.490 595.720 555.950 596.770 ;
        RECT 556.790 595.720 558.250 596.770 ;
        RECT 559.090 595.720 560.550 596.770 ;
        RECT 561.390 595.720 562.850 596.770 ;
        RECT 563.690 595.720 565.150 596.770 ;
        RECT 565.990 595.720 567.450 596.770 ;
        RECT 568.290 595.720 569.750 596.770 ;
        RECT 570.590 595.720 572.050 596.770 ;
        RECT 572.890 595.720 574.350 596.770 ;
        RECT 575.190 595.720 591.920 596.770 ;
        RECT 4.690 4.280 591.920 595.720 ;
        RECT 4.690 4.000 74.330 4.280 ;
        RECT 75.170 4.000 224.290 4.280 ;
        RECT 225.130 4.000 374.250 4.280 ;
        RECT 375.090 4.000 524.210 4.280 ;
        RECT 525.050 4.000 591.920 4.280 ;
      LAYER met3 ;
        RECT 3.990 574.960 596.000 587.685 ;
        RECT 4.400 573.560 596.000 574.960 ;
        RECT 3.990 538.240 596.000 573.560 ;
        RECT 4.400 536.840 596.000 538.240 ;
        RECT 3.990 501.520 596.000 536.840 ;
        RECT 4.400 500.120 596.000 501.520 ;
        RECT 3.990 464.800 596.000 500.120 ;
        RECT 4.400 463.400 596.000 464.800 ;
        RECT 3.990 428.080 596.000 463.400 ;
        RECT 4.400 426.680 596.000 428.080 ;
        RECT 3.990 391.360 596.000 426.680 ;
        RECT 4.400 389.960 596.000 391.360 ;
        RECT 3.990 354.640 596.000 389.960 ;
        RECT 4.400 353.240 596.000 354.640 ;
        RECT 3.990 317.920 596.000 353.240 ;
        RECT 4.400 316.520 596.000 317.920 ;
        RECT 3.990 300.240 596.000 316.520 ;
        RECT 3.990 298.840 595.600 300.240 ;
        RECT 3.990 281.200 596.000 298.840 ;
        RECT 4.400 279.800 596.000 281.200 ;
        RECT 3.990 244.480 596.000 279.800 ;
        RECT 4.400 243.080 596.000 244.480 ;
        RECT 3.990 207.760 596.000 243.080 ;
        RECT 4.400 206.360 596.000 207.760 ;
        RECT 3.990 171.040 596.000 206.360 ;
        RECT 4.400 169.640 596.000 171.040 ;
        RECT 3.990 134.320 596.000 169.640 ;
        RECT 4.400 132.920 596.000 134.320 ;
        RECT 3.990 97.600 596.000 132.920 ;
        RECT 4.400 96.200 596.000 97.600 ;
        RECT 3.990 60.880 596.000 96.200 ;
        RECT 4.400 59.480 596.000 60.880 ;
        RECT 3.990 24.160 596.000 59.480 ;
        RECT 4.400 22.760 596.000 24.160 ;
        RECT 3.990 10.715 596.000 22.760 ;
      LAYER met4 ;
        RECT 37.095 11.735 174.240 585.985 ;
        RECT 176.640 11.735 177.540 585.985 ;
        RECT 179.940 11.735 327.840 585.985 ;
        RECT 330.240 11.735 331.140 585.985 ;
        RECT 333.540 11.735 446.825 585.985 ;
  END
END highpass
END LIBRARY

